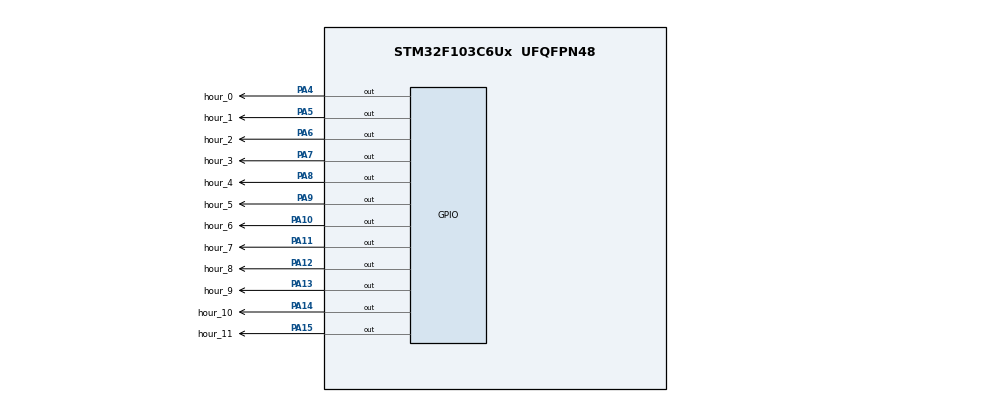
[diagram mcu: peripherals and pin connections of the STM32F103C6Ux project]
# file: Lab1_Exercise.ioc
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Mcu.Family=STM32F1
Mcu.Name=STM32F103C6Ux
Mcu.Package=UFQFPN48
NVIC.PriorityGroup=NVIC_PRIORITYGROUP_4
PA10.GPIO_Label=hour_6
PA10.Signal=GPIO_Output
PA11.GPIO_Label=hour_7
PA11.Signal=GPIO_Output
PA12.GPIO_Label=hour_8
PA12.Signal=GPIO_Output
PA13.GPIO_Label=hour_9
PA13.Signal=GPIO_Output
PA14.GPIO_Label=hour_10
PA14.Signal=GPIO_Output
PA15.GPIO_Label=hour_11
PA15.Signal=GPIO_Output
PA4.GPIO_Label=hour_0
PA4.Signal=GPIO_Output
PA5.GPIO_Label=hour_1
PA5.Signal=GPIO_Output
PA6.GPIO_Label=hour_2
PA6.Signal=GPIO_Output
PA7.GPIO_Label=hour_3
PA7.Signal=GPIO_Output
PA8.GPIO_Label=hour_4
PA8.Signal=GPIO_Output
PA9.GPIO_Label=hour_5
PA9.Signal=GPIO_Output
ProjectManager.HeapSize=0x200
ProjectManager.StackSize=0x400
ProjectManager.TargetToolchain=STM32CubeIDE
RCC.APB1Freq_Value=8000000
RCC.APB2Freq_Value=8000000
board=custom

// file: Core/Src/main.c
/* USER CODE BEGIN Header */
/**
  ******************************************************************************
  * @file           : main.c
  * @brief          : Main program body
  ******************************************************************************
  * @attention
  *
  * Copyright (c) 2023 STMicroelectronics.
  * All rights reserved.
  *
  * This software is licensed under terms that can be found in the LICENSE file
  * in the root directory of this software component.
  * If no LICENSE file comes with this software, it is provided AS-IS.
  *
  ******************************************************************************
  */
/* USER CODE END Header */
#include "main.h"

/* USER CODE BEGIN PD */
enum color{red, yellow, green};
/* USER CODE END PD */

/* USER CODE BEGIN PM */
#define red_counter 5
#define yellow_counter 2
#define green_counter 3
/* USER CODE END PM */

/* USER CODE BEGIN PV */
GPIO_TypeDef *light_port[1][3] = {
		{LED_RED_GPIO_Port, LED_YELLOW_GPIO_Port, LED_GREEN_GPIO_Port}
};
uint16_t light_pin[1][3] = {
		{LED_RED_Pin, LED_YELLOW_Pin, LED_GREEN_Pin}
};
/* USER CODE END PV */

void SystemClock_Config(void);
static void MX_GPIO_Init(void);
/* USER CODE BEGIN PFP */
void on_light(enum color light, int cluster);
/* USER CODE END PFP */

/* USER CODE BEGIN 0 */
void on_light(enum color light, int cluster)
{
    cluster--;
    switch (light)
    {
    case red:
        HAL_GPIO_WritePin(light_port[cluster][red], light_pin[cluster][red], RESET);
        HAL_GPIO_WritePin(light_port[cluster][yellow], light_pin[cluster][yellow], SET);
        HAL_GPIO_WritePin(light_port[cluster][green], light_pin[cluster][green], SET);
        break;
    case yellow:
        HAL_GPIO_WritePin(light_port[cluster][red], light_pin[cluster][red], SET);
        HAL_GPIO_WritePin(light_port[cluster][yellow], light_pin[cluster][yellow], RESET);
        HAL_GPIO_WritePin(light_port[cluster][green], light_pin[cluster][green], SET);
        break;
    default:
        HAL_GPIO_WritePin(light_port[cluster][red], light_pin[cluster][red], SET);
        HAL_GPIO_WritePin(light_port[cluster][yellow], light_pin[cluster][yellow], SET);
        HAL_GPIO_WritePin(light_port[cluster][green], light_pin[cluster][green], RESET);
    }
}
/* USER CODE END 0 */

int main(void)
{
  /* USER CODE BEGIN 1 */
	enum color status = yellow;
	int timer_counter = yellow_counter;
  /* USER CODE END 1 */

  /* MCU Configuration--------------------------------------------------------*/

  /* Reset of all peripherals, Initializes the Flash interface and the Systick. */
  HAL_Init();

  /* Configure the system clock */
  SystemClock_Config();

  /* Initialize all configured peripherals */
  MX_GPIO_Init();
  /* USER CODE BEGIN 2 */
  on_light(yellow, 1);
  /* USER CODE END 2 */

  /* Infinite loop */
  /* USER CODE BEGIN WHILE */
  while (1)
  {
	  switch (status)
	  {
	  case red:
		  if(timer_counter <= 0)
		  {
			  status = green;
			  timer_counter = green_counter;
			  on_light(green, 1);
		  }
		  break;
	  case green:
		  if(timer_counter <= 0)
		  {
			  status = yellow;
			  timer_counter = yellow_counter;
			  on_light(yellow, 1);
		  }
		  break;
	  default:
		  if(timer_counter <= 0)
		  {
			  status = red;
			  timer_counter = red_counter;
			  on_light(red, 1);
		  }
	  }
	  timer_counter--;
	  HAL_Delay(1000);
    /* USER CODE END WHILE */

  }
}

void SystemClock_Config(void)
{
  RCC_OscInitTypeDef RCC_OscInitStruct = {0};
  RCC_ClkInitTypeDef RCC_ClkInitStruct = {0};

  /** Initializes the RCC Oscillators according to the specified parameters
  * in the RCC_OscInitTypeDef structure.
  */
  RCC_OscInitStruct.OscillatorType = RCC_OSCILLATORTYPE_HSI;
  RCC_OscInitStruct.HSIState = RCC_HSI_ON;
  RCC_OscInitStruct.HSICalibrationValue = RCC_HSICALIBRATION_DEFAULT;
  RCC_OscInitStruct.PLL.PLLState = RCC_PLL_NONE;
  if (HAL_RCC_OscConfig(&RCC_OscInitStruct) != HAL_OK)
  {
    Error_Handler();
  }

  /** Initializes the CPU, AHB and APB buses clocks
  */
  RCC_ClkInitStruct.ClockType = RCC_CLOCKTYPE_HCLK|RCC_CLOCKTYPE_SYSCLK
                              |RCC_CLOCKTYPE_PCLK1|RCC_CLOCKTYPE_PCLK2;
  RCC_ClkInitStruct.SYSCLKSource = RCC_SYSCLKSOURCE_HSI;
  RCC_ClkInitStruct.AHBCLKDivider = RCC_SYSCLK_DIV1;
  RCC_ClkInitStruct.APB1CLKDivider = RCC_HCLK_DIV1;
  RCC_ClkInitStruct.APB2CLKDivider = RCC_HCLK_DIV1;

  if (HAL_RCC_ClockConfig(&RCC_ClkInitStruct, FLASH_LATENCY_0) != HAL_OK)
  {
    Error_Handler();
  }
}

static void MX_GPIO_Init(void)
{
  GPIO_InitTypeDef GPIO_InitStruct = {0};

  /* GPIO Ports Clock Enable */
  __HAL_RCC_GPIOA_CLK_ENABLE();

  /*Configure GPIO pin Output Level */
  HAL_GPIO_WritePin(GPIOA, LED_RED_Pin|LED_YELLOW_Pin|LED_GREEN_Pin, GPIO_PIN_RESET);

  /*Configure GPIO pins : LED_RED_Pin LED_YELLOW_Pin LED_GREEN_Pin */
  GPIO_InitStruct.Pin = LED_RED_Pin|LED_YELLOW_Pin|LED_GREEN_Pin;
  GPIO_InitStruct.Mode = GPIO_MODE_OUTPUT_PP;
  GPIO_InitStruct.Pull = GPIO_NOPULL;
  GPIO_InitStruct.Speed = GPIO_SPEED_FREQ_LOW;
  HAL_GPIO_Init(GPIOA, &GPIO_InitStruct);

}

void Error_Handler(void)
{
  __disable_irq();
  while (1)
  {
  }
}
